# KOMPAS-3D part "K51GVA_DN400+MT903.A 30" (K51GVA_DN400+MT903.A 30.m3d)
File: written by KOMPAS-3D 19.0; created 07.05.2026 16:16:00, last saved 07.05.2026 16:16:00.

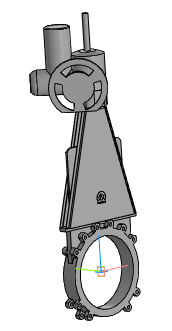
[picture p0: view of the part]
Document properties: Автор: Энергия; Полное имя файла: ..\K51GVA_DN50-DN1000+MT903.A\K51GVA_DN400+MT903.A 30.a3d

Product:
- Part/product: K51GVA_DN400+MT903.A 30
    Масса: 244.985

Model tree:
1. Операция без истории:1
